# Generated by FakeRAM 2.0
VERSION 5.7 ;
BUSBITCHARS "[]" ;
PROPERTYDEFINITIONS
  MACRO width INTEGER ;
  MACRO depth INTEGER ;
  MACRO banks INTEGER ;
END PROPERTYDEFINITIONS
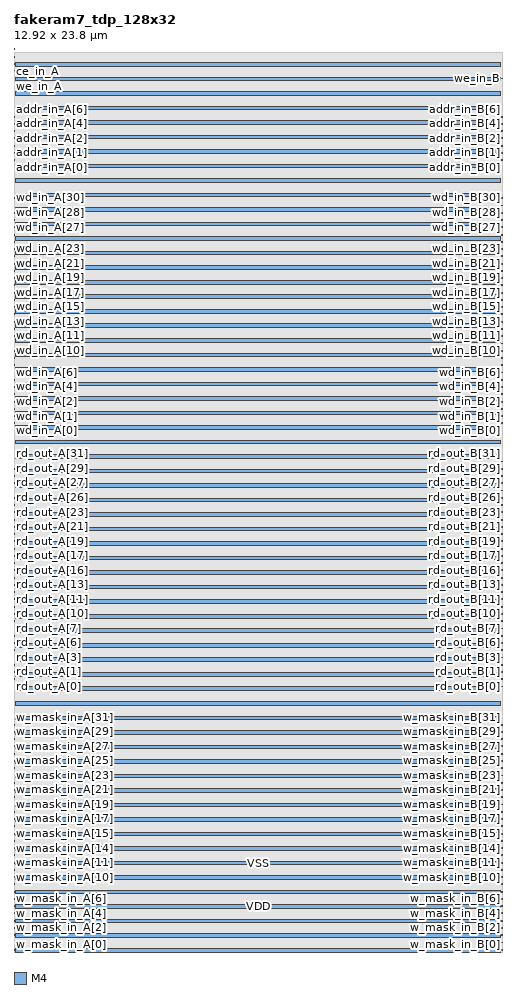
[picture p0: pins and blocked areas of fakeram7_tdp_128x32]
MACRO fakeram7_tdp_128x32
  PROPERTY width 32 ;
  PROPERTY depth 128 ;
  PROPERTY banks 2 ;
  FOREIGN fakeram7_tdp_128x32 0 0 ;
  SYMMETRY X Y ;
  SIZE 12.920 BY 23.800 ;
  CLASS BLOCK ;
  PIN w_mask_in_A[0]
    DIRECTION INPUT ;
    USE SIGNAL ;
    SHAPE ABUTMENT ;
    PORT
      LAYER M4 ;
      RECT 0.000 0.048 0.024 0.072 ;
    END
  END w_mask_in_A[0]
  PIN w_mask_in_B[0]
    DIRECTION INPUT ;
    USE SIGNAL ;
    SHAPE ABUTMENT ;
    PORT
      LAYER M4 ;
      RECT 12.896 0.048 12.920 0.072 ;
    END
  END w_mask_in_B[0]
  PIN w_mask_in_A[1]
    DIRECTION INPUT ;
    USE SIGNAL ;
    SHAPE ABUTMENT ;
    PORT
      LAYER M4 ;
      RECT 0.000 0.240 0.024 0.264 ;
    END
  END w_mask_in_A[1]
  PIN w_mask_in_B[1]
    DIRECTION INPUT ;
    USE SIGNAL ;
    SHAPE ABUTMENT ;
    PORT
      LAYER M4 ;
      RECT 12.896 0.240 12.920 0.264 ;
    END
  END w_mask_in_B[1]
  PIN w_mask_in_A[2]
    DIRECTION INPUT ;
    USE SIGNAL ;
    SHAPE ABUTMENT ;
    PORT
      LAYER M4 ;
      RECT 0.000 0.432 0.024 0.456 ;
    END
  END w_mask_in_A[2]
  PIN w_mask_in_B[2]
    DIRECTION INPUT ;
    USE SIGNAL ;
    SHAPE ABUTMENT ;
    PORT
      LAYER M4 ;
      RECT 12.896 0.432 12.920 0.456 ;
    END
  END w_mask_in_B[2]
  PIN w_mask_in_A[3]
    DIRECTION INPUT ;
    USE SIGNAL ;
    SHAPE ABUTMENT ;
    PORT
      LAYER M4 ;
      RECT 0.000 0.624 0.024 0.648 ;
    END
  END w_mask_in_A[3]
  PIN w_mask_in_B[3]
    DIRECTION INPUT ;
    USE SIGNAL ;
    SHAPE ABUTMENT ;
    PORT
      LAYER M4 ;
      RECT 12.896 0.624 12.920 0.648 ;
    END
  END w_mask_in_B[3]
  PIN w_mask_in_A[4]
    DIRECTION INPUT ;
    USE SIGNAL ;
    SHAPE ABUTMENT ;
    PORT
      LAYER M4 ;
      RECT 0.000 0.816 0.024 0.840 ;
    END
  END w_mask_in_A[4]
  PIN w_mask_in_B[4]
    DIRECTION INPUT ;
    USE SIGNAL ;
    SHAPE ABUTMENT ;
    PORT
      LAYER M4 ;
      RECT 12.896 0.816 12.920 0.840 ;
    END
  END w_mask_in_B[4]
  PIN w_mask_in_A[5]
    DIRECTION INPUT ;
    USE SIGNAL ;
    SHAPE ABUTMENT ;
    PORT
      LAYER M4 ;
      RECT 0.000 1.008 0.024 1.032 ;
    END
  END w_mask_in_A[5]
  PIN w_mask_in_B[5]
    DIRECTION INPUT ;
    USE SIGNAL ;
    SHAPE ABUTMENT ;
    PORT
      LAYER M4 ;
      RECT 12.896 1.008 12.920 1.032 ;
    END
  END w_mask_in_B[5]
  PIN w_mask_in_A[6]
    DIRECTION INPUT ;
    USE SIGNAL ;
    SHAPE ABUTMENT ;
    PORT
      LAYER M4 ;
      RECT 0.000 1.200 0.024 1.224 ;
    END
  END w_mask_in_A[6]
  PIN w_mask_in_B[6]
    DIRECTION INPUT ;
    USE SIGNAL ;
    SHAPE ABUTMENT ;
    PORT
      LAYER M4 ;
      RECT 12.896 1.200 12.920 1.224 ;
    END
  END w_mask_in_B[6]
  PIN w_mask_in_A[7]
    DIRECTION INPUT ;
    USE SIGNAL ;
    SHAPE ABUTMENT ;
    PORT
      LAYER M4 ;
      RECT 0.000 1.392 0.024 1.416 ;
    END
  END w_mask_in_A[7]
  PIN w_mask_in_B[7]
    DIRECTION INPUT ;
    USE SIGNAL ;
    SHAPE ABUTMENT ;
    PORT
      LAYER M4 ;
      RECT 12.896 1.392 12.920 1.416 ;
    END
  END w_mask_in_B[7]
  PIN w_mask_in_A[8]
    DIRECTION INPUT ;
    USE SIGNAL ;
    SHAPE ABUTMENT ;
    PORT
      LAYER M4 ;
      RECT 0.000 1.584 0.024 1.608 ;
    END
  END w_mask_in_A[8]
  PIN w_mask_in_B[8]
    DIRECTION INPUT ;
    USE SIGNAL ;
    SHAPE ABUTMENT ;
    PORT
      LAYER M4 ;
      RECT 12.896 1.584 12.920 1.608 ;
    END
  END w_mask_in_B[8]
  PIN w_mask_in_A[9]
    DIRECTION INPUT ;
    USE SIGNAL ;
    SHAPE ABUTMENT ;
    PORT
      LAYER M4 ;
      RECT 0.000 1.776 0.024 1.800 ;
    END
  END w_mask_in_A[9]
  PIN w_mask_in_B[9]
    DIRECTION INPUT ;
    USE SIGNAL ;
    SHAPE ABUTMENT ;
    PORT
      LAYER M4 ;
      RECT 12.896 1.776 12.920 1.800 ;
    END
  END w_mask_in_B[9]
  PIN w_mask_in_A[10]
    DIRECTION INPUT ;
    USE SIGNAL ;
    SHAPE ABUTMENT ;
    PORT
      LAYER M4 ;
      RECT 0.000 1.968 0.024 1.992 ;
    END
  END w_mask_in_A[10]
  PIN w_mask_in_B[10]
    DIRECTION INPUT ;
    USE SIGNAL ;
    SHAPE ABUTMENT ;
    PORT
      LAYER M4 ;
      RECT 12.896 1.968 12.920 1.992 ;
    END
  END w_mask_in_B[10]
  PIN w_mask_in_A[11]
    DIRECTION INPUT ;
    USE SIGNAL ;
    SHAPE ABUTMENT ;
    PORT
      LAYER M4 ;
      RECT 0.000 2.160 0.024 2.184 ;
    END
  END w_mask_in_A[11]
  PIN w_mask_in_B[11]
    DIRECTION INPUT ;
    USE SIGNAL ;
    SHAPE ABUTMENT ;
    PORT
      LAYER M4 ;
      RECT 12.896 2.160 12.920 2.184 ;
    END
  END w_mask_in_B[11]
  PIN w_mask_in_A[12]
    DIRECTION INPUT ;
    USE SIGNAL ;
    SHAPE ABUTMENT ;
    PORT
      LAYER M4 ;
      RECT 0.000 2.352 0.024 2.376 ;
    END
  END w_mask_in_A[12]
  PIN w_mask_in_B[12]
    DIRECTION INPUT ;
    USE SIGNAL ;
    SHAPE ABUTMENT ;
    PORT
      LAYER M4 ;
      RECT 12.896 2.352 12.920 2.376 ;
    END
  END w_mask_in_B[12]
  PIN w_mask_in_A[13]
    DIRECTION INPUT ;
    USE SIGNAL ;
    SHAPE ABUTMENT ;
    PORT
      LAYER M4 ;
      RECT 0.000 2.544 0.024 2.568 ;
    END
  END w_mask_in_A[13]
  PIN w_mask_in_B[13]
    DIRECTION INPUT ;
    USE SIGNAL ;
    SHAPE ABUTMENT ;
    PORT
      LAYER M4 ;
      RECT 12.896 2.544 12.920 2.568 ;
    END
  END w_mask_in_B[13]
  PIN w_mask_in_A[14]
    DIRECTION INPUT ;
    USE SIGNAL ;
    SHAPE ABUTMENT ;
    PORT
      LAYER M4 ;
      RECT 0.000 2.736 0.024 2.760 ;
    END
  END w_mask_in_A[14]
  PIN w_mask_in_B[14]
    DIRECTION INPUT ;
    USE SIGNAL ;
    SHAPE ABUTMENT ;
    PORT
      LAYER M4 ;
      RECT 12.896 2.736 12.920 2.760 ;
    END
  END w_mask_in_B[14]
  PIN w_mask_in_A[15]
    DIRECTION INPUT ;
    USE SIGNAL ;
    SHAPE ABUTMENT ;
    PORT
      LAYER M4 ;
      RECT 0.000 2.928 0.024 2.952 ;
    END
  END w_mask_in_A[15]
  PIN w_mask_in_B[15]
    DIRECTION INPUT ;
    USE SIGNAL ;
    SHAPE ABUTMENT ;
    PORT
      LAYER M4 ;
      RECT 12.896 2.928 12.920 2.952 ;
    END
  END w_mask_in_B[15]
  PIN w_mask_in_A[16]
    DIRECTION INPUT ;
    USE SIGNAL ;
    SHAPE ABUTMENT ;
    PORT
      LAYER M4 ;
      RECT 0.000 3.120 0.024 3.144 ;
    END
  END w_mask_in_A[16]
  PIN w_mask_in_B[16]
    DIRECTION INPUT ;
    USE SIGNAL ;
    SHAPE ABUTMENT ;
    PORT
      LAYER M4 ;
      RECT 12.896 3.120 12.920 3.144 ;
    END
  END w_mask_in_B[16]
  PIN w_mask_in_A[17]
    DIRECTION INPUT ;
    USE SIGNAL ;
    SHAPE ABUTMENT ;
    PORT
      LAYER M4 ;
      RECT 0.000 3.312 0.024 3.336 ;
    END
  END w_mask_in_A[17]
  PIN w_mask_in_B[17]
    DIRECTION INPUT ;
    USE SIGNAL ;
    SHAPE ABUTMENT ;
    PORT
      LAYER M4 ;
      RECT 12.896 3.312 12.920 3.336 ;
    END
  END w_mask_in_B[17]
  PIN w_mask_in_A[18]
    DIRECTION INPUT ;
    USE SIGNAL ;
    SHAPE ABUTMENT ;
    PORT
      LAYER M4 ;
      RECT 0.000 3.504 0.024 3.528 ;
    END
  END w_mask_in_A[18]
  PIN w_mask_in_B[18]
    DIRECTION INPUT ;
    USE SIGNAL ;
    SHAPE ABUTMENT ;
    PORT
      LAYER M4 ;
      RECT 12.896 3.504 12.920 3.528 ;
    END
  END w_mask_in_B[18]
  PIN w_mask_in_A[19]
    DIRECTION INPUT ;
    USE SIGNAL ;
    SHAPE ABUTMENT ;
    PORT
      LAYER M4 ;
      RECT 0.000 3.696 0.024 3.720 ;
    END
  END w_mask_in_A[19]
  PIN w_mask_in_B[19]
    DIRECTION INPUT ;
    USE SIGNAL ;
    SHAPE ABUTMENT ;
    PORT
      LAYER M4 ;
      RECT 12.896 3.696 12.920 3.720 ;
    END
  END w_mask_in_B[19]
  PIN w_mask_in_A[20]
    DIRECTION INPUT ;
    USE SIGNAL ;
    SHAPE ABUTMENT ;
    PORT
      LAYER M4 ;
      RECT 0.000 3.888 0.024 3.912 ;
    END
  END w_mask_in_A[20]
  PIN w_mask_in_B[20]
    DIRECTION INPUT ;
    USE SIGNAL ;
    SHAPE ABUTMENT ;
    PORT
      LAYER M4 ;
      RECT 12.896 3.888 12.920 3.912 ;
    END
  END w_mask_in_B[20]
  PIN w_mask_in_A[21]
    DIRECTION INPUT ;
    USE SIGNAL ;
    SHAPE ABUTMENT ;
    PORT
      LAYER M4 ;
      RECT 0.000 4.080 0.024 4.104 ;
    END
  END w_mask_in_A[21]
  PIN w_mask_in_B[21]
    DIRECTION INPUT ;
    USE SIGNAL ;
    SHAPE ABUTMENT ;
    PORT
      LAYER M4 ;
      RECT 12.896 4.080 12.920 4.104 ;
    END
  END w_mask_in_B[21]
  PIN w_mask_in_A[22]
    DIRECTION INPUT ;
    USE SIGNAL ;
    SHAPE ABUTMENT ;
    PORT
      LAYER M4 ;
      RECT 0.000 4.272 0.024 4.296 ;
    END
  END w_mask_in_A[22]
  PIN w_mask_in_B[22]
    DIRECTION INPUT ;
    USE SIGNAL ;
    SHAPE ABUTMENT ;
    PORT
      LAYER M4 ;
      RECT 12.896 4.272 12.920 4.296 ;
    END
  END w_mask_in_B[22]
  PIN w_mask_in_A[23]
    DIRECTION INPUT ;
    USE SIGNAL ;
    SHAPE ABUTMENT ;
    PORT
      LAYER M4 ;
      RECT 0.000 4.464 0.024 4.488 ;
    END
  END w_mask_in_A[23]
  PIN w_mask_in_B[23]
    DIRECTION INPUT ;
    USE SIGNAL ;
    SHAPE ABUTMENT ;
    PORT
      LAYER M4 ;
      RECT 12.896 4.464 12.920 4.488 ;
    END
  END w_mask_in_B[23]
  PIN w_mask_in_A[24]
    DIRECTION INPUT ;
    USE SIGNAL ;
    SHAPE ABUTMENT ;
    PORT
      LAYER M4 ;
      RECT 0.000 4.656 0.024 4.680 ;
    END
  END w_mask_in_A[24]
  PIN w_mask_in_B[24]
    DIRECTION INPUT ;
    USE SIGNAL ;
    SHAPE ABUTMENT ;
    PORT
      LAYER M4 ;
      RECT 12.896 4.656 12.920 4.680 ;
    END
  END w_mask_in_B[24]
  PIN w_mask_in_A[25]
    DIRECTION INPUT ;
    USE SIGNAL ;
    SHAPE ABUTMENT ;
    PORT
      LAYER M4 ;
      RECT 0.000 4.848 0.024 4.872 ;
    END
  END w_mask_in_A[25]
  PIN w_mask_in_B[25]
    DIRECTION INPUT ;
    USE SIGNAL ;
    SHAPE ABUTMENT ;
    PORT
      LAYER M4 ;
      RECT 12.896 4.848 12.920 4.872 ;
    END
  END w_mask_in_B[25]
  PIN w_mask_in_A[26]
    DIRECTION INPUT ;
    USE SIGNAL ;
    SHAPE ABUTMENT ;
    PORT
      LAYER M4 ;
      RECT 0.000 5.040 0.024 5.064 ;
    END
  END w_mask_in_A[26]
  PIN w_mask_in_B[26]
    DIRECTION INPUT ;
    USE SIGNAL ;
    SHAPE ABUTMENT ;
    PORT
      LAYER M4 ;
      RECT 12.896 5.040 12.920 5.064 ;
    END
  END w_mask_in_B[26]
  PIN w_mask_in_A[27]
    DIRECTION INPUT ;
    USE SIGNAL ;
    SHAPE ABUTMENT ;
    PORT
      LAYER M4 ;
      RECT 0.000 5.232 0.024 5.256 ;
    END
  END w_mask_in_A[27]
  PIN w_mask_in_B[27]
    DIRECTION INPUT ;
    USE SIGNAL ;
    SHAPE ABUTMENT ;
    PORT
      LAYER M4 ;
      RECT 12.896 5.232 12.920 5.256 ;
    END
  END w_mask_in_B[27]
  PIN w_mask_in_A[28]
    DIRECTION INPUT ;
    USE SIGNAL ;
    SHAPE ABUTMENT ;
    PORT
      LAYER M4 ;
      RECT 0.000 5.424 0.024 5.448 ;
    END
  END w_mask_in_A[28]
  PIN w_mask_in_B[28]
    DIRECTION INPUT ;
    USE SIGNAL ;
    SHAPE ABUTMENT ;
    PORT
      LAYER M4 ;
      RECT 12.896 5.424 12.920 5.448 ;
    END
  END w_mask_in_B[28]
  PIN w_mask_in_A[29]
    DIRECTION INPUT ;
    USE SIGNAL ;
    SHAPE ABUTMENT ;
    PORT
      LAYER M4 ;
      RECT 0.000 5.616 0.024 5.640 ;
    END
  END w_mask_in_A[29]
  PIN w_mask_in_B[29]
    DIRECTION INPUT ;
    USE SIGNAL ;
    SHAPE ABUTMENT ;
    PORT
      LAYER M4 ;
      RECT 12.896 5.616 12.920 5.640 ;
    END
  END w_mask_in_B[29]
  PIN w_mask_in_A[30]
    DIRECTION INPUT ;
    USE SIGNAL ;
    SHAPE ABUTMENT ;
    PORT
      LAYER M4 ;
      RECT 0.000 5.808 0.024 5.832 ;
    END
  END w_mask_in_A[30]
  PIN w_mask_in_B[30]
    DIRECTION INPUT ;
    USE SIGNAL ;
    SHAPE ABUTMENT ;
    PORT
      LAYER M4 ;
      RECT 12.896 5.808 12.920 5.832 ;
    END
  END w_mask_in_B[30]
  PIN w_mask_in_A[31]
    DIRECTION INPUT ;
    USE SIGNAL ;
    SHAPE ABUTMENT ;
    PORT
      LAYER M4 ;
      RECT 0.000 6.000 0.024 6.024 ;
    END
  END w_mask_in_A[31]
  PIN w_mask_in_B[31]
    DIRECTION INPUT ;
    USE SIGNAL ;
    SHAPE ABUTMENT ;
    PORT
      LAYER M4 ;
      RECT 12.896 6.000 12.920 6.024 ;
    END
  END w_mask_in_B[31]
  PIN rd_out_A[0]
    DIRECTION OUTPUT ;
    USE SIGNAL ;
    SHAPE ABUTMENT ;
    PORT
      LAYER M4 ;
      RECT 0.000 7.008 0.024 7.032 ;
    END
  END rd_out_A[0]
  PIN rd_out_B[0]
    DIRECTION OUTPUT ;
    USE SIGNAL ;
    SHAPE ABUTMENT ;
    PORT
      LAYER M4 ;
      RECT 12.896 7.008 12.920 7.032 ;
    END
  END rd_out_B[0]
  PIN rd_out_A[1]
    DIRECTION OUTPUT ;
    USE SIGNAL ;
    SHAPE ABUTMENT ;
    PORT
      LAYER M4 ;
      RECT 0.000 7.200 0.024 7.224 ;
    END
  END rd_out_A[1]
  PIN rd_out_B[1]
    DIRECTION OUTPUT ;
    USE SIGNAL ;
    SHAPE ABUTMENT ;
    PORT
      LAYER M4 ;
      RECT 12.896 7.200 12.920 7.224 ;
    END
  END rd_out_B[1]
  PIN rd_out_A[2]
    DIRECTION OUTPUT ;
    USE SIGNAL ;
    SHAPE ABUTMENT ;
    PORT
      LAYER M4 ;
      RECT 0.000 7.392 0.024 7.416 ;
    END
  END rd_out_A[2]
  PIN rd_out_B[2]
    DIRECTION OUTPUT ;
    USE SIGNAL ;
    SHAPE ABUTMENT ;
    PORT
      LAYER M4 ;
      RECT 12.896 7.392 12.920 7.416 ;
    END
  END rd_out_B[2]
  PIN rd_out_A[3]
    DIRECTION OUTPUT ;
    USE SIGNAL ;
    SHAPE ABUTMENT ;
    PORT
      LAYER M4 ;
      RECT 0.000 7.584 0.024 7.608 ;
    END
  END rd_out_A[3]
  PIN rd_out_B[3]
    DIRECTION OUTPUT ;
    USE SIGNAL ;
    SHAPE ABUTMENT ;
    PORT
      LAYER M4 ;
      RECT 12.896 7.584 12.920 7.608 ;
    END
  END rd_out_B[3]
  PIN rd_out_A[4]
    DIRECTION OUTPUT ;
    USE SIGNAL ;
    SHAPE ABUTMENT ;
    PORT
      LAYER M4 ;
      RECT 0.000 7.776 0.024 7.800 ;
    END
  END rd_out_A[4]
  PIN rd_out_B[4]
    DIRECTION OUTPUT ;
    USE SIGNAL ;
    SHAPE ABUTMENT ;
    PORT
      LAYER M4 ;
      RECT 12.896 7.776 12.920 7.800 ;
    END
  END rd_out_B[4]
  PIN rd_out_A[5]
    DIRECTION OUTPUT ;
    USE SIGNAL ;
    SHAPE ABUTMENT ;
    PORT
      LAYER M4 ;
      RECT 0.000 7.968 0.024 7.992 ;
    END
  END rd_out_A[5]
  PIN rd_out_B[5]
    DIRECTION OUTPUT ;
    USE SIGNAL ;
    SHAPE ABUTMENT ;
    PORT
      LAYER M4 ;
      RECT 12.896 7.968 12.920 7.992 ;
    END
  END rd_out_B[5]
  PIN rd_out_A[6]
    DIRECTION OUTPUT ;
    USE SIGNAL ;
    SHAPE ABUTMENT ;
    PORT
      LAYER M4 ;
      RECT 0.000 8.160 0.024 8.184 ;
    END
  END rd_out_A[6]
  PIN rd_out_B[6]
    DIRECTION OUTPUT ;
    USE SIGNAL ;
    SHAPE ABUTMENT ;
    PORT
      LAYER M4 ;
      RECT 12.896 8.160 12.920 8.184 ;
    END
  END rd_out_B[6]
  PIN rd_out_A[7]
    DIRECTION OUTPUT ;
    USE SIGNAL ;
    SHAPE ABUTMENT ;
    PORT
      LAYER M4 ;
      RECT 0.000 8.352 0.024 8.376 ;
    END
  END rd_out_A[7]
  PIN rd_out_B[7]
    DIRECTION OUTPUT ;
    USE SIGNAL ;
    SHAPE ABUTMENT ;
    PORT
      LAYER M4 ;
      RECT 12.896 8.352 12.920 8.376 ;
    END
  END rd_out_B[7]
  PIN rd_out_A[8]
    DIRECTION OUTPUT ;
    USE SIGNAL ;
    SHAPE ABUTMENT ;
    PORT
      LAYER M4 ;
      RECT 0.000 8.544 0.024 8.568 ;
    END
  END rd_out_A[8]
  PIN rd_out_B[8]
    DIRECTION OUTPUT ;
    USE SIGNAL ;
    SHAPE ABUTMENT ;
    PORT
      LAYER M4 ;
      RECT 12.896 8.544 12.920 8.568 ;
    END
  END rd_out_B[8]
  PIN rd_out_A[9]
    DIRECTION OUTPUT ;
    USE SIGNAL ;
    SHAPE ABUTMENT ;
    PORT
      LAYER M4 ;
      RECT 0.000 8.736 0.024 8.760 ;
    END
  END rd_out_A[9]
  PIN rd_out_B[9]
    DIRECTION OUTPUT ;
    USE SIGNAL ;
    SHAPE ABUTMENT ;
    PORT
      LAYER M4 ;
      RECT 12.896 8.736 12.920 8.760 ;
    END
  END rd_out_B[9]
  PIN rd_out_A[10]
    DIRECTION OUTPUT ;
    USE SIGNAL ;
    SHAPE ABUTMENT ;
    PORT
      LAYER M4 ;
      RECT 0.000 8.928 0.024 8.952 ;
    END
  END rd_out_A[10]
  PIN rd_out_B[10]
    DIRECTION OUTPUT ;
    USE SIGNAL ;
    SHAPE ABUTMENT ;
    PORT
      LAYER M4 ;
      RECT 12.896 8.928 12.920 8.952 ;
    END
  END rd_out_B[10]
  PIN rd_out_A[11]
    DIRECTION OUTPUT ;
    USE SIGNAL ;
    SHAPE ABUTMENT ;
    PORT
      LAYER M4 ;
      RECT 0.000 9.120 0.024 9.144 ;
    END
  END rd_out_A[11]
  PIN rd_out_B[11]
    DIRECTION OUTPUT ;
    USE SIGNAL ;
    SHAPE ABUTMENT ;
    PORT
      LAYER M4 ;
      RECT 12.896 9.120 12.920 9.144 ;
    END
  END rd_out_B[11]
  PIN rd_out_A[12]
    DIRECTION OUTPUT ;
    USE SIGNAL ;
    SHAPE ABUTMENT ;
    PORT
      LAYER M4 ;
      RECT 0.000 9.312 0.024 9.336 ;
    END
  END rd_out_A[12]
  PIN rd_out_B[12]
    DIRECTION OUTPUT ;
    USE SIGNAL ;
    SHAPE ABUTMENT ;
    PORT
      LAYER M4 ;
      RECT 12.896 9.312 12.920 9.336 ;
    END
  END rd_out_B[12]
  PIN rd_out_A[13]
    DIRECTION OUTPUT ;
    USE SIGNAL ;
    SHAPE ABUTMENT ;
    PORT
      LAYER M4 ;
      RECT 0.000 9.504 0.024 9.528 ;
    END
  END rd_out_A[13]
  PIN rd_out_B[13]
    DIRECTION OUTPUT ;
    USE SIGNAL ;
    SHAPE ABUTMENT ;
    PORT
      LAYER M4 ;
      RECT 12.896 9.504 12.920 9.528 ;
    END
  END rd_out_B[13]
  PIN rd_out_A[14]
    DIRECTION OUTPUT ;
    USE SIGNAL ;
    SHAPE ABUTMENT ;
    PORT
      LAYER M4 ;
      RECT 0.000 9.696 0.024 9.720 ;
    END
  END rd_out_A[14]
  PIN rd_out_B[14]
    DIRECTION OUTPUT ;
    USE SIGNAL ;
    SHAPE ABUTMENT ;
    PORT
      LAYER M4 ;
      RECT 12.896 9.696 12.920 9.720 ;
    END
  END rd_out_B[14]
  PIN rd_out_A[15]
    DIRECTION OUTPUT ;
    USE SIGNAL ;
    SHAPE ABUTMENT ;
    PORT
      LAYER M4 ;
      RECT 0.000 9.888 0.024 9.912 ;
    END
  END rd_out_A[15]
  PIN rd_out_B[15]
    DIRECTION OUTPUT ;
    USE SIGNAL ;
    SHAPE ABUTMENT ;
    PORT
      LAYER M4 ;
      RECT 12.896 9.888 12.920 9.912 ;
    END
  END rd_out_B[15]
  PIN rd_out_A[16]
    DIRECTION OUTPUT ;
    USE SIGNAL ;
    SHAPE ABUTMENT ;
    PORT
      LAYER M4 ;
      RECT 0.000 10.080 0.024 10.104 ;
    END
  END rd_out_A[16]
  PIN rd_out_B[16]
    DIRECTION OUTPUT ;
    USE SIGNAL ;
    SHAPE ABUTMENT ;
    PORT
      LAYER M4 ;
      RECT 12.896 10.080 12.920 10.104 ;
    END
  END rd_out_B[16]
  PIN rd_out_A[17]
    DIRECTION OUTPUT ;
    USE SIGNAL ;
    SHAPE ABUTMENT ;
    PORT
      LAYER M4 ;
      RECT 0.000 10.272 0.024 10.296 ;
    END
  END rd_out_A[17]
  PIN rd_out_B[17]
    DIRECTION OUTPUT ;
    USE SIGNAL ;
    SHAPE ABUTMENT ;
    PORT
      LAYER M4 ;
      RECT 12.896 10.272 12.920 10.296 ;
    END
  END rd_out_B[17]
  PIN rd_out_A[18]
    DIRECTION OUTPUT ;
    USE SIGNAL ;
    SHAPE ABUTMENT ;
    PORT
      LAYER M4 ;
      RECT 0.000 10.464 0.024 10.488 ;
    END
  END rd_out_A[18]
  PIN rd_out_B[18]
    DIRECTION OUTPUT ;
    USE SIGNAL ;
    SHAPE ABUTMENT ;
    PORT
      LAYER M4 ;
      RECT 12.896 10.464 12.920 10.488 ;
    END
  END rd_out_B[18]
  PIN rd_out_A[19]
    DIRECTION OUTPUT ;
    USE SIGNAL ;
    SHAPE ABUTMENT ;
    PORT
      LAYER M4 ;
      RECT 0.000 10.656 0.024 10.680 ;
    END
  END rd_out_A[19]
  PIN rd_out_B[19]
    DIRECTION OUTPUT ;
    USE SIGNAL ;
    SHAPE ABUTMENT ;
    PORT
      LAYER M4 ;
      RECT 12.896 10.656 12.920 10.680 ;
    END
  END rd_out_B[19]
  PIN rd_out_A[20]
    DIRECTION OUTPUT ;
    USE SIGNAL ;
    SHAPE ABUTMENT ;
    PORT
      LAYER M4 ;
      RECT 0.000 10.848 0.024 10.872 ;
    END
  END rd_out_A[20]
  PIN rd_out_B[20]
    DIRECTION OUTPUT ;
    USE SIGNAL ;
    SHAPE ABUTMENT ;
    PORT
      LAYER M4 ;
      RECT 12.896 10.848 12.920 10.872 ;
    END
  END rd_out_B[20]
  PIN rd_out_A[21]
    DIRECTION OUTPUT ;
    USE SIGNAL ;
    SHAPE ABUTMENT ;
    PORT
      LAYER M4 ;
      RECT 0.000 11.040 0.024 11.064 ;
    END
  END rd_out_A[21]
  PIN rd_out_B[21]
    DIRECTION OUTPUT ;
    USE SIGNAL ;
    SHAPE ABUTMENT ;
    PORT
      LAYER M4 ;
      RECT 12.896 11.040 12.920 11.064 ;
    END
  END rd_out_B[21]
  PIN rd_out_A[22]
    DIRECTION OUTPUT ;
    USE SIGNAL ;
    SHAPE ABUTMENT ;
    PORT
      LAYER M4 ;
      RECT 0.000 11.232 0.024 11.256 ;
    END
  END rd_out_A[22]
  PIN rd_out_B[22]
    DIRECTION OUTPUT ;
    USE SIGNAL ;
    SHAPE ABUTMENT ;
    PORT
      LAYER M4 ;
      RECT 12.896 11.232 12.920 11.256 ;
    END
  END rd_out_B[22]
  PIN rd_out_A[23]
    DIRECTION OUTPUT ;
    USE SIGNAL ;
    SHAPE ABUTMENT ;
    PORT
      LAYER M4 ;
      RECT 0.000 11.424 0.024 11.448 ;
    END
  END rd_out_A[23]
  PIN rd_out_B[23]
    DIRECTION OUTPUT ;
    USE SIGNAL ;
    SHAPE ABUTMENT ;
    PORT
      LAYER M4 ;
      RECT 12.896 11.424 12.920 11.448 ;
    END
  END rd_out_B[23]
  PIN rd_out_A[24]
    DIRECTION OUTPUT ;
    USE SIGNAL ;
    SHAPE ABUTMENT ;
    PORT
      LAYER M4 ;
      RECT 0.000 11.616 0.024 11.640 ;
    END
  END rd_out_A[24]
  PIN rd_out_B[24]
    DIRECTION OUTPUT ;
    USE SIGNAL ;
    SHAPE ABUTMENT ;
    PORT
      LAYER M4 ;
      RECT 12.896 11.616 12.920 11.640 ;
    END
  END rd_out_B[24]
  PIN rd_out_A[25]
    DIRECTION OUTPUT ;
    USE SIGNAL ;
    SHAPE ABUTMENT ;
    PORT
      LAYER M4 ;
      RECT 0.000 11.808 0.024 11.832 ;
    END
  END rd_out_A[25]
  PIN rd_out_B[25]
    DIRECTION OUTPUT ;
    USE SIGNAL ;
    SHAPE ABUTMENT ;
    PORT
      LAYER M4 ;
      RECT 12.896 11.808 12.920 11.832 ;
    END
  END rd_out_B[25]
  PIN rd_out_A[26]
    DIRECTION OUTPUT ;
    USE SIGNAL ;
    SHAPE ABUTMENT ;
    PORT
      LAYER M4 ;
      RECT 0.000 12.000 0.024 12.024 ;
    END
  END rd_out_A[26]
  PIN rd_out_B[26]
    DIRECTION OUTPUT ;
    USE SIGNAL ;
    SHAPE ABUTMENT ;
    PORT
      LAYER M4 ;
      RECT 12.896 12.000 12.920 12.024 ;
    END
  END rd_out_B[26]
  PIN rd_out_A[27]
    DIRECTION OUTPUT ;
    USE SIGNAL ;
    SHAPE ABUTMENT ;
    PORT
      LAYER M4 ;
      RECT 0.000 12.192 0.024 12.216 ;
    END
  END rd_out_A[27]
  PIN rd_out_B[27]
    DIRECTION OUTPUT ;
    USE SIGNAL ;
    SHAPE ABUTMENT ;
    PORT
      LAYER M4 ;
      RECT 12.896 12.192 12.920 12.216 ;
    END
  END rd_out_B[27]
  PIN rd_out_A[28]
    DIRECTION OUTPUT ;
    USE SIGNAL ;
    SHAPE ABUTMENT ;
    PORT
      LAYER M4 ;
      RECT 0.000 12.384 0.024 12.408 ;
    END
  END rd_out_A[28]
  PIN rd_out_B[28]
    DIRECTION OUTPUT ;
    USE SIGNAL ;
    SHAPE ABUTMENT ;
    PORT
      LAYER M4 ;
      RECT 12.896 12.384 12.920 12.408 ;
    END
  END rd_out_B[28]
  PIN rd_out_A[29]
    DIRECTION OUTPUT ;
    USE SIGNAL ;
    SHAPE ABUTMENT ;
    PORT
      LAYER M4 ;
      RECT 0.000 12.576 0.024 12.600 ;
    END
  END rd_out_A[29]
  PIN rd_out_B[29]
    DIRECTION OUTPUT ;
    USE SIGNAL ;
    SHAPE ABUTMENT ;
    PORT
      LAYER M4 ;
      RECT 12.896 12.576 12.920 12.600 ;
    END
  END rd_out_B[29]
  PIN rd_out_A[30]
    DIRECTION OUTPUT ;
    USE SIGNAL ;
    SHAPE ABUTMENT ;
    PORT
      LAYER M4 ;
      RECT 0.000 12.768 0.024 12.792 ;
    END
  END rd_out_A[30]
  PIN rd_out_B[30]
    DIRECTION OUTPUT ;
    USE SIGNAL ;
    SHAPE ABUTMENT ;
    PORT
      LAYER M4 ;
      RECT 12.896 12.768 12.920 12.792 ;
    END
  END rd_out_B[30]
  PIN rd_out_A[31]
    DIRECTION OUTPUT ;
    USE SIGNAL ;
    SHAPE ABUTMENT ;
    PORT
      LAYER M4 ;
      RECT 0.000 12.960 0.024 12.984 ;
    END
  END rd_out_A[31]
  PIN rd_out_B[31]
    DIRECTION OUTPUT ;
    USE SIGNAL ;
    SHAPE ABUTMENT ;
    PORT
      LAYER M4 ;
      RECT 12.896 12.960 12.920 12.984 ;
    END
  END rd_out_B[31]
  PIN wd_in_A[0]
    DIRECTION INPUT ;
    USE SIGNAL ;
    SHAPE ABUTMENT ;
    PORT
      LAYER M4 ;
      RECT 0.000 13.968 0.024 13.992 ;
    END
  END wd_in_A[0]
  PIN wd_in_B[0]
    DIRECTION INPUT ;
    USE SIGNAL ;
    SHAPE ABUTMENT ;
    PORT
      LAYER M4 ;
      RECT 12.896 13.968 12.920 13.992 ;
    END
  END wd_in_B[0]
  PIN wd_in_A[1]
    DIRECTION INPUT ;
    USE SIGNAL ;
    SHAPE ABUTMENT ;
    PORT
      LAYER M4 ;
      RECT 0.000 14.160 0.024 14.184 ;
    END
  END wd_in_A[1]
  PIN wd_in_B[1]
    DIRECTION INPUT ;
    USE SIGNAL ;
    SHAPE ABUTMENT ;
    PORT
      LAYER M4 ;
      RECT 12.896 14.160 12.920 14.184 ;
    END
  END wd_in_B[1]
  PIN wd_in_A[2]
    DIRECTION INPUT ;
    USE SIGNAL ;
    SHAPE ABUTMENT ;
    PORT
      LAYER M4 ;
      RECT 0.000 14.352 0.024 14.376 ;
    END
  END wd_in_A[2]
  PIN wd_in_B[2]
    DIRECTION INPUT ;
    USE SIGNAL ;
    SHAPE ABUTMENT ;
    PORT
      LAYER M4 ;
      RECT 12.896 14.352 12.920 14.376 ;
    END
  END wd_in_B[2]
  PIN wd_in_A[3]
    DIRECTION INPUT ;
    USE SIGNAL ;
    SHAPE ABUTMENT ;
    PORT
      LAYER M4 ;
      RECT 0.000 14.544 0.024 14.568 ;
    END
  END wd_in_A[3]
  PIN wd_in_B[3]
    DIRECTION INPUT ;
    USE SIGNAL ;
    SHAPE ABUTMENT ;
    PORT
      LAYER M4 ;
      RECT 12.896 14.544 12.920 14.568 ;
    END
  END wd_in_B[3]
  PIN wd_in_A[4]
    DIRECTION INPUT ;
    USE SIGNAL ;
    SHAPE ABUTMENT ;
    PORT
      LAYER M4 ;
      RECT 0.000 14.736 0.024 14.760 ;
    END
  END wd_in_A[4]
  PIN wd_in_B[4]
    DIRECTION INPUT ;
    USE SIGNAL ;
    SHAPE ABUTMENT ;
    PORT
      LAYER M4 ;
      RECT 12.896 14.736 12.920 14.760 ;
    END
  END wd_in_B[4]
  PIN wd_in_A[5]
    DIRECTION INPUT ;
    USE SIGNAL ;
    SHAPE ABUTMENT ;
    PORT
      LAYER M4 ;
      RECT 0.000 14.928 0.024 14.952 ;
    END
  END wd_in_A[5]
  PIN wd_in_B[5]
    DIRECTION INPUT ;
    USE SIGNAL ;
    SHAPE ABUTMENT ;
    PORT
      LAYER M4 ;
      RECT 12.896 14.928 12.920 14.952 ;
    END
  END wd_in_B[5]
  PIN wd_in_A[6]
    DIRECTION INPUT ;
    USE SIGNAL ;
    SHAPE ABUTMENT ;
    PORT
      LAYER M4 ;
      RECT 0.000 15.120 0.024 15.144 ;
    END
  END wd_in_A[6]
  PIN wd_in_B[6]
    DIRECTION INPUT ;
    USE SIGNAL ;
    SHAPE ABUTMENT ;
    PORT
      LAYER M4 ;
      RECT 12.896 15.120 12.920 15.144 ;
    END
  END wd_in_B[6]
  PIN wd_in_A[7]
    DIRECTION INPUT ;
    USE SIGNAL ;
    SHAPE ABUTMENT ;
    PORT
      LAYER M4 ;
      RECT 0.000 15.312 0.024 15.336 ;
    END
  END wd_in_A[7]
  PIN wd_in_B[7]
    DIRECTION INPUT ;
    USE SIGNAL ;
    SHAPE ABUTMENT ;
    PORT
      LAYER M4 ;
      RECT 12.896 15.312 12.920 15.336 ;
    END
  END wd_in_B[7]
  PIN wd_in_A[8]
    DIRECTION INPUT ;
    USE SIGNAL ;
    SHAPE ABUTMENT ;
    PORT
      LAYER M4 ;
      RECT 0.000 15.504 0.024 15.528 ;
    END
  END wd_in_A[8]
  PIN wd_in_B[8]
    DIRECTION INPUT ;
    USE SIGNAL ;
    SHAPE ABUTMENT ;
    PORT
      LAYER M4 ;
      RECT 12.896 15.504 12.920 15.528 ;
    END
  END wd_in_B[8]
  PIN wd_in_A[9]
    DIRECTION INPUT ;
    USE SIGNAL ;
    SHAPE ABUTMENT ;
    PORT
      LAYER M4 ;
      RECT 0.000 15.696 0.024 15.720 ;
    END
  END wd_in_A[9]
  PIN wd_in_B[9]
    DIRECTION INPUT ;
    USE SIGNAL ;
    SHAPE ABUTMENT ;
    PORT
      LAYER M4 ;
      RECT 12.896 15.696 12.920 15.720 ;
    END
  END wd_in_B[9]
  PIN wd_in_A[10]
    DIRECTION INPUT ;
    USE SIGNAL ;
    SHAPE ABUTMENT ;
    PORT
      LAYER M4 ;
      RECT 0.000 15.888 0.024 15.912 ;
    END
  END wd_in_A[10]
  PIN wd_in_B[10]
    DIRECTION INPUT ;
    USE SIGNAL ;
    SHAPE ABUTMENT ;
    PORT
      LAYER M4 ;
      RECT 12.896 15.888 12.920 15.912 ;
    END
  END wd_in_B[10]
  PIN wd_in_A[11]
    DIRECTION INPUT ;
    USE SIGNAL ;
    SHAPE ABUTMENT ;
    PORT
      LAYER M4 ;
      RECT 0.000 16.080 0.024 16.104 ;
    END
  END wd_in_A[11]
  PIN wd_in_B[11]
    DIRECTION INPUT ;
    USE SIGNAL ;
    SHAPE ABUTMENT ;
    PORT
      LAYER M4 ;
      RECT 12.896 16.080 12.920 16.104 ;
    END
  END wd_in_B[11]
  PIN wd_in_A[12]
    DIRECTION INPUT ;
    USE SIGNAL ;
    SHAPE ABUTMENT ;
    PORT
      LAYER M4 ;
      RECT 0.000 16.272 0.024 16.296 ;
    END
  END wd_in_A[12]
  PIN wd_in_B[12]
    DIRECTION INPUT ;
    USE SIGNAL ;
    SHAPE ABUTMENT ;
    PORT
      LAYER M4 ;
      RECT 12.896 16.272 12.920 16.296 ;
    END
  END wd_in_B[12]
  PIN wd_in_A[13]
    DIRECTION INPUT ;
    USE SIGNAL ;
    SHAPE ABUTMENT ;
    PORT
      LAYER M4 ;
      RECT 0.000 16.464 0.024 16.488 ;
    END
  END wd_in_A[13]
  PIN wd_in_B[13]
    DIRECTION INPUT ;
    USE SIGNAL ;
    SHAPE ABUTMENT ;
    PORT
      LAYER M4 ;
      RECT 12.896 16.464 12.920 16.488 ;
    END
  END wd_in_B[13]
  PIN wd_in_A[14]
    DIRECTION INPUT ;
    USE SIGNAL ;
    SHAPE ABUTMENT ;
    PORT
      LAYER M4 ;
      RECT 0.000 16.656 0.024 16.680 ;
    END
  END wd_in_A[14]
  PIN wd_in_B[14]
    DIRECTION INPUT ;
    USE SIGNAL ;
    SHAPE ABUTMENT ;
    PORT
      LAYER M4 ;
      RECT 12.896 16.656 12.920 16.680 ;
    END
  END wd_in_B[14]
  PIN wd_in_A[15]
    DIRECTION INPUT ;
    USE SIGNAL ;
    SHAPE ABUTMENT ;
    PORT
      LAYER M4 ;
      RECT 0.000 16.848 0.024 16.872 ;
    END
  END wd_in_A[15]
  PIN wd_in_B[15]
    DIRECTION INPUT ;
    USE SIGNAL ;
    SHAPE ABUTMENT ;
    PORT
      LAYER M4 ;
      RECT 12.896 16.848 12.920 16.872 ;
    END
  END wd_in_B[15]
  PIN wd_in_A[16]
    DIRECTION INPUT ;
    USE SIGNAL ;
    SHAPE ABUTMENT ;
    PORT
      LAYER M4 ;
      RECT 0.000 17.040 0.024 17.064 ;
    END
  END wd_in_A[16]
  PIN wd_in_B[16]
    DIRECTION INPUT ;
    USE SIGNAL ;
    SHAPE ABUTMENT ;
    PORT
      LAYER M4 ;
      RECT 12.896 17.040 12.920 17.064 ;
    END
  END wd_in_B[16]
  PIN wd_in_A[17]
    DIRECTION INPUT ;
    USE SIGNAL ;
    SHAPE ABUTMENT ;
    PORT
      LAYER M4 ;
      RECT 0.000 17.232 0.024 17.256 ;
    END
  END wd_in_A[17]
  PIN wd_in_B[17]
    DIRECTION INPUT ;
    USE SIGNAL ;
    SHAPE ABUTMENT ;
    PORT
      LAYER M4 ;
      RECT 12.896 17.232 12.920 17.256 ;
    END
  END wd_in_B[17]
  PIN wd_in_A[18]
    DIRECTION INPUT ;
    USE SIGNAL ;
    SHAPE ABUTMENT ;
    PORT
      LAYER M4 ;
      RECT 0.000 17.424 0.024 17.448 ;
    END
  END wd_in_A[18]
  PIN wd_in_B[18]
    DIRECTION INPUT ;
    USE SIGNAL ;
    SHAPE ABUTMENT ;
    PORT
      LAYER M4 ;
      RECT 12.896 17.424 12.920 17.448 ;
    END
  END wd_in_B[18]
  PIN wd_in_A[19]
    DIRECTION INPUT ;
    USE SIGNAL ;
    SHAPE ABUTMENT ;
    PORT
      LAYER M4 ;
      RECT 0.000 17.616 0.024 17.640 ;
    END
  END wd_in_A[19]
  PIN wd_in_B[19]
    DIRECTION INPUT ;
    USE SIGNAL ;
    SHAPE ABUTMENT ;
    PORT
      LAYER M4 ;
      RECT 12.896 17.616 12.920 17.640 ;
    END
  END wd_in_B[19]
  PIN wd_in_A[20]
    DIRECTION INPUT ;
    USE SIGNAL ;
    SHAPE ABUTMENT ;
    PORT
      LAYER M4 ;
      RECT 0.000 17.808 0.024 17.832 ;
    END
  END wd_in_A[20]
  PIN wd_in_B[20]
    DIRECTION INPUT ;
    USE SIGNAL ;
    SHAPE ABUTMENT ;
    PORT
      LAYER M4 ;
      RECT 12.896 17.808 12.920 17.832 ;
    END
  END wd_in_B[20]
  PIN wd_in_A[21]
    DIRECTION INPUT ;
    USE SIGNAL ;
    SHAPE ABUTMENT ;
    PORT
      LAYER M4 ;
      RECT 0.000 18.000 0.024 18.024 ;
    END
  END wd_in_A[21]
  PIN wd_in_B[21]
    DIRECTION INPUT ;
    USE SIGNAL ;
    SHAPE ABUTMENT ;
    PORT
      LAYER M4 ;
      RECT 12.896 18.000 12.920 18.024 ;
    END
  END wd_in_B[21]
  PIN wd_in_A[22]
    DIRECTION INPUT ;
    USE SIGNAL ;
    SHAPE ABUTMENT ;
    PORT
      LAYER M4 ;
      RECT 0.000 18.192 0.024 18.216 ;
    END
  END wd_in_A[22]
  PIN wd_in_B[22]
    DIRECTION INPUT ;
    USE SIGNAL ;
    SHAPE ABUTMENT ;
    PORT
      LAYER M4 ;
      RECT 12.896 18.192 12.920 18.216 ;
    END
  END wd_in_B[22]
  PIN wd_in_A[23]
    DIRECTION INPUT ;
    USE SIGNAL ;
    SHAPE ABUTMENT ;
    PORT
      LAYER M4 ;
      RECT 0.000 18.384 0.024 18.408 ;
    END
  END wd_in_A[23]
  PIN wd_in_B[23]
    DIRECTION INPUT ;
    USE SIGNAL ;
    SHAPE ABUTMENT ;
    PORT
      LAYER M4 ;
      RECT 12.896 18.384 12.920 18.408 ;
    END
  END wd_in_B[23]
  PIN wd_in_A[24]
    DIRECTION INPUT ;
    USE SIGNAL ;
    SHAPE ABUTMENT ;
    PORT
      LAYER M4 ;
      RECT 0.000 18.576 0.024 18.600 ;
    END
  END wd_in_A[24]
  PIN wd_in_B[24]
    DIRECTION INPUT ;
    USE SIGNAL ;
    SHAPE ABUTMENT ;
    PORT
      LAYER M4 ;
      RECT 12.896 18.576 12.920 18.600 ;
    END
  END wd_in_B[24]
  PIN wd_in_A[25]
    DIRECTION INPUT ;
    USE SIGNAL ;
    SHAPE ABUTMENT ;
    PORT
      LAYER M4 ;
      RECT 0.000 18.768 0.024 18.792 ;
    END
  END wd_in_A[25]
  PIN wd_in_B[25]
    DIRECTION INPUT ;
    USE SIGNAL ;
    SHAPE ABUTMENT ;
    PORT
      LAYER M4 ;
      RECT 12.896 18.768 12.920 18.792 ;
    END
  END wd_in_B[25]
  PIN wd_in_A[26]
    DIRECTION INPUT ;
    USE SIGNAL ;
    SHAPE ABUTMENT ;
    PORT
      LAYER M4 ;
      RECT 0.000 18.960 0.024 18.984 ;
    END
  END wd_in_A[26]
  PIN wd_in_B[26]
    DIRECTION INPUT ;
    USE SIGNAL ;
    SHAPE ABUTMENT ;
    PORT
      LAYER M4 ;
      RECT 12.896 18.960 12.920 18.984 ;
    END
  END wd_in_B[26]
  PIN wd_in_A[27]
    DIRECTION INPUT ;
    USE SIGNAL ;
    SHAPE ABUTMENT ;
    PORT
      LAYER M4 ;
      RECT 0.000 19.152 0.024 19.176 ;
    END
  END wd_in_A[27]
  PIN wd_in_B[27]
    DIRECTION INPUT ;
    USE SIGNAL ;
    SHAPE ABUTMENT ;
    PORT
      LAYER M4 ;
      RECT 12.896 19.152 12.920 19.176 ;
    END
  END wd_in_B[27]
  PIN wd_in_A[28]
    DIRECTION INPUT ;
    USE SIGNAL ;
    SHAPE ABUTMENT ;
    PORT
      LAYER M4 ;
      RECT 0.000 19.344 0.024 19.368 ;
    END
  END wd_in_A[28]
  PIN wd_in_B[28]
    DIRECTION INPUT ;
    USE SIGNAL ;
    SHAPE ABUTMENT ;
    PORT
      LAYER M4 ;
      RECT 12.896 19.344 12.920 19.368 ;
    END
  END wd_in_B[28]
  PIN wd_in_A[29]
    DIRECTION INPUT ;
    USE SIGNAL ;
    SHAPE ABUTMENT ;
    PORT
      LAYER M4 ;
      RECT 0.000 19.536 0.024 19.560 ;
    END
  END wd_in_A[29]
  PIN wd_in_B[29]
    DIRECTION INPUT ;
    USE SIGNAL ;
    SHAPE ABUTMENT ;
    PORT
      LAYER M4 ;
      RECT 12.896 19.536 12.920 19.560 ;
    END
  END wd_in_B[29]
  PIN wd_in_A[30]
    DIRECTION INPUT ;
    USE SIGNAL ;
    SHAPE ABUTMENT ;
    PORT
      LAYER M4 ;
      RECT 0.000 19.728 0.024 19.752 ;
    END
  END wd_in_A[30]
  PIN wd_in_B[30]
    DIRECTION INPUT ;
    USE SIGNAL ;
    SHAPE ABUTMENT ;
    PORT
      LAYER M4 ;
      RECT 12.896 19.728 12.920 19.752 ;
    END
  END wd_in_B[30]
  PIN wd_in_A[31]
    DIRECTION INPUT ;
    USE SIGNAL ;
    SHAPE ABUTMENT ;
    PORT
      LAYER M4 ;
      RECT 0.000 19.920 0.024 19.944 ;
    END
  END wd_in_A[31]
  PIN wd_in_B[31]
    DIRECTION INPUT ;
    USE SIGNAL ;
    SHAPE ABUTMENT ;
    PORT
      LAYER M4 ;
      RECT 12.896 19.920 12.920 19.944 ;
    END
  END wd_in_B[31]
  PIN addr_in_A[0]
    DIRECTION INPUT ;
    USE SIGNAL ;
    SHAPE ABUTMENT ;
    PORT
      LAYER M4 ;
      RECT 0.000 20.928 0.024 20.952 ;
    END
  END addr_in_A[0]
  PIN addr_in_B[0]
    DIRECTION INPUT ;
    USE SIGNAL ;
    SHAPE ABUTMENT ;
    PORT
      LAYER M4 ;
      RECT 12.896 20.928 12.920 20.952 ;
    END
  END addr_in_B[0]
  PIN addr_in_A[1]
    DIRECTION INPUT ;
    USE SIGNAL ;
    SHAPE ABUTMENT ;
    PORT
      LAYER M4 ;
      RECT 0.000 21.120 0.024 21.144 ;
    END
  END addr_in_A[1]
  PIN addr_in_B[1]
    DIRECTION INPUT ;
    USE SIGNAL ;
    SHAPE ABUTMENT ;
    PORT
      LAYER M4 ;
      RECT 12.896 21.120 12.920 21.144 ;
    END
  END addr_in_B[1]
  PIN addr_in_A[2]
    DIRECTION INPUT ;
    USE SIGNAL ;
    SHAPE ABUTMENT ;
    PORT
      LAYER M4 ;
      RECT 0.000 21.312 0.024 21.336 ;
    END
  END addr_in_A[2]
  PIN addr_in_B[2]
    DIRECTION INPUT ;
    USE SIGNAL ;
    SHAPE ABUTMENT ;
    PORT
      LAYER M4 ;
      RECT 12.896 21.312 12.920 21.336 ;
    END
  END addr_in_B[2]
  PIN addr_in_A[3]
    DIRECTION INPUT ;
    USE SIGNAL ;
    SHAPE ABUTMENT ;
    PORT
      LAYER M4 ;
      RECT 0.000 21.504 0.024 21.528 ;
    END
  END addr_in_A[3]
  PIN addr_in_B[3]
    DIRECTION INPUT ;
    USE SIGNAL ;
    SHAPE ABUTMENT ;
    PORT
      LAYER M4 ;
      RECT 12.896 21.504 12.920 21.528 ;
    END
  END addr_in_B[3]
  PIN addr_in_A[4]
    DIRECTION INPUT ;
    USE SIGNAL ;
    SHAPE ABUTMENT ;
    PORT
      LAYER M4 ;
      RECT 0.000 21.696 0.024 21.720 ;
    END
  END addr_in_A[4]
  PIN addr_in_B[4]
    DIRECTION INPUT ;
    USE SIGNAL ;
    SHAPE ABUTMENT ;
    PORT
      LAYER M4 ;
      RECT 12.896 21.696 12.920 21.720 ;
    END
  END addr_in_B[4]
  PIN addr_in_A[5]
    DIRECTION INPUT ;
    USE SIGNAL ;
    SHAPE ABUTMENT ;
    PORT
      LAYER M4 ;
      RECT 0.000 21.888 0.024 21.912 ;
    END
  END addr_in_A[5]
  PIN addr_in_B[5]
    DIRECTION INPUT ;
    USE SIGNAL ;
    SHAPE ABUTMENT ;
    PORT
      LAYER M4 ;
      RECT 12.896 21.888 12.920 21.912 ;
    END
  END addr_in_B[5]
  PIN addr_in_A[6]
    DIRECTION INPUT ;
    USE SIGNAL ;
    SHAPE ABUTMENT ;
    PORT
      LAYER M4 ;
      RECT 0.000 22.080 0.024 22.104 ;
    END
  END addr_in_A[6]
  PIN addr_in_B[6]
    DIRECTION INPUT ;
    USE SIGNAL ;
    SHAPE ABUTMENT ;
    PORT
      LAYER M4 ;
      RECT 12.896 22.080 12.920 22.104 ;
    END
  END addr_in_B[6]
  PIN we_in_A
    DIRECTION INPUT ;
    USE SIGNAL ;
    SHAPE ABUTMENT ;
    PORT
      LAYER M4 ;
      RECT 0.000 23.088 0.024 23.112 ;
    END
  END we_in_A
  PIN we_in_B
    DIRECTION INPUT ;
    USE SIGNAL ;
    SHAPE ABUTMENT ;
    PORT
      LAYER M4 ;
      RECT 12.896 23.088 12.920 23.112 ;
    END
  END we_in_B
  PIN ce_in_A
    DIRECTION INPUT ;
    USE SIGNAL ;
    SHAPE ABUTMENT ;
    PORT
      LAYER M4 ;
      RECT 0.000 23.280 0.024 23.304 ;
    END
  END ce_in_A
  PIN clk_A
    DIRECTION INPUT ;
    USE SIGNAL ;
    SHAPE ABUTMENT ;
    PORT
      LAYER M4 ;
      RECT 0.000 23.472 0.024 23.496 ;
    END
  END clk_A
  PIN ce_in_B
    DIRECTION INPUT ;
    USE SIGNAL ;
    SHAPE ABUTMENT ;
    PORT
      LAYER M4 ;
      RECT 0.000 23.664 0.024 23.688 ;
    END
  END ce_in_B
  PIN clk_B
    DIRECTION INPUT ;
    USE SIGNAL ;
    SHAPE ABUTMENT ;
    PORT
      LAYER M4 ;
      RECT 0.000 23.856 0.024 23.880 ;
    END
  END clk_B
  PIN VSS
    DIRECTION INOUT ;
    USE GROUND ;
    PORT
      LAYER M4 ;
      RECT 0.048 0.000 12.872 0.096 ;
      RECT 0.048 0.768 12.872 0.864 ;
      RECT 0.048 1.536 12.872 1.632 ;
      RECT 0.048 2.304 12.872 2.400 ;
      RECT 0.048 3.072 12.872 3.168 ;
      RECT 0.048 3.840 12.872 3.936 ;
      RECT 0.048 4.608 12.872 4.704 ;
      RECT 0.048 5.376 12.872 5.472 ;
      RECT 0.048 6.144 12.872 6.240 ;
      RECT 0.048 6.912 12.872 7.008 ;
      RECT 0.048 7.680 12.872 7.776 ;
      RECT 0.048 8.448 12.872 8.544 ;
      RECT 0.048 9.216 12.872 9.312 ;
      RECT 0.048 9.984 12.872 10.080 ;
      RECT 0.048 10.752 12.872 10.848 ;
      RECT 0.048 11.520 12.872 11.616 ;
      RECT 0.048 12.288 12.872 12.384 ;
      RECT 0.048 13.056 12.872 13.152 ;
      RECT 0.048 13.824 12.872 13.920 ;
      RECT 0.048 14.592 12.872 14.688 ;
      RECT 0.048 15.360 12.872 15.456 ;
      RECT 0.048 16.128 12.872 16.224 ;
      RECT 0.048 16.896 12.872 16.992 ;
      RECT 0.048 17.664 12.872 17.760 ;
      RECT 0.048 18.432 12.872 18.528 ;
      RECT 0.048 19.200 12.872 19.296 ;
      RECT 0.048 19.968 12.872 20.064 ;
      RECT 0.048 20.736 12.872 20.832 ;
      RECT 0.048 21.504 12.872 21.600 ;
      RECT 0.048 22.272 12.872 22.368 ;
      RECT 0.048 23.040 12.872 23.136 ;
    END
  END VSS
  PIN VDD
    DIRECTION INOUT ;
    USE POWER ;
    PORT
      LAYER M4 ;
      RECT 0.048 0.384 12.872 0.480 ;
      RECT 0.048 1.152 12.872 1.248 ;
      RECT 0.048 1.920 12.872 2.016 ;
      RECT 0.048 2.688 12.872 2.784 ;
      RECT 0.048 3.456 12.872 3.552 ;
      RECT 0.048 4.224 12.872 4.320 ;
      RECT 0.048 4.992 12.872 5.088 ;
      RECT 0.048 5.760 12.872 5.856 ;
      RECT 0.048 6.528 12.872 6.624 ;
      RECT 0.048 7.296 12.872 7.392 ;
      RECT 0.048 8.064 12.872 8.160 ;
      RECT 0.048 8.832 12.872 8.928 ;
      RECT 0.048 9.600 12.872 9.696 ;
      RECT 0.048 10.368 12.872 10.464 ;
      RECT 0.048 11.136 12.872 11.232 ;
      RECT 0.048 11.904 12.872 12.000 ;
      RECT 0.048 12.672 12.872 12.768 ;
      RECT 0.048 13.440 12.872 13.536 ;
      RECT 0.048 14.208 12.872 14.304 ;
      RECT 0.048 14.976 12.872 15.072 ;
      RECT 0.048 15.744 12.872 15.840 ;
      RECT 0.048 16.512 12.872 16.608 ;
      RECT 0.048 17.280 12.872 17.376 ;
      RECT 0.048 18.048 12.872 18.144 ;
      RECT 0.048 18.816 12.872 18.912 ;
      RECT 0.048 19.584 12.872 19.680 ;
      RECT 0.048 20.352 12.872 20.448 ;
      RECT 0.048 21.120 12.872 21.216 ;
      RECT 0.048 21.888 12.872 21.984 ;
      RECT 0.048 22.656 12.872 22.752 ;
      RECT 0.048 23.424 12.872 23.520 ;
    END
  END VDD
  OBS
    LAYER M1 ;
    RECT 0 0 12.920 23.800 ;
    LAYER M2 ;
    RECT 0 0 12.920 23.800 ;
    LAYER M3 ;
    RECT 0 0 12.920 23.800 ;
    LAYER M4 ;
    RECT 0 0 12.920 23.800 ;
  END
END fakeram7_tdp_128x32

END LIBRARY
